MANUFACTURINGGRID 0.005 ;

LAYER OVERLAP
    TYPE OVERLAP ;
END OVERLAP

LAYER LOCKED
    TYPE MASTERSLICE ;
END LOCKED

LAYER LOCKED1
    TYPE MASTERSLICE ;
END LOCKED1

LAYER LOCKED2
    TYPE MASTERSLICE ;
END LOCKED2

LAYER GatPoly
    TYPE MASTERSLICE ;
END GatPoly

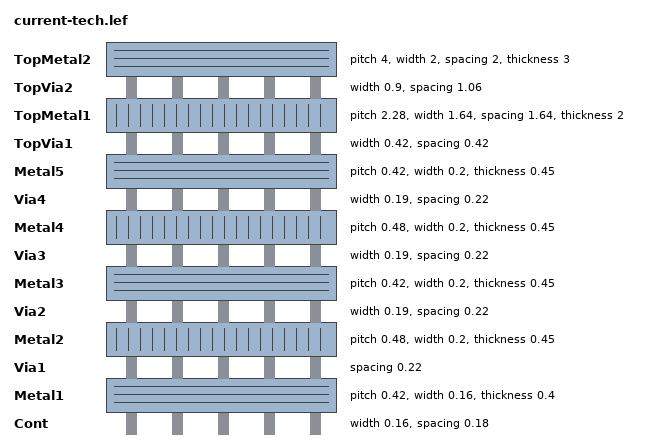
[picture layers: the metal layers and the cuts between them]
LAYER Cont
    TYPE CUT ;
    WIDTH 0.16 ;
    SPACING 0.18  ;
    ANTENNACUMAREARATIO 30 ;
    ANTENNACUMDIFFAREARATIO 10000 ;
    RESISTANCE 22 ;
END Cont

LAYER Metal1
    TYPE ROUTING ;
    PITCH 0.42 ;
    WIDTH 0.16 ;
    AREA 0.09 ;
    THICKNESS 0.4 ;
    MAXWIDTH 30 ;
SPACINGTABLE
  PARALLELRUNLENGTH 0.000 1.000 10.000
  WIDTH 0.000	 0.180 0.180 0.180
  WIDTH 0.300	 0.180 0.220 0.220
  WIDTH 10.000	 0.180 0.220 0.600 ;
    MINIMUMCUT 2  WIDTH 1.4 ;
    ANTENNACUMAREARATIO 200 ;
    ANTENNACUMDIFFAREARATIO  PWL ( ( 0 200 ) ( 0.159 200 ) ( 0.16 3200 ) ( 100 2e+06 ) ) ;
    DIRECTION HORIZONTAL ;
    RESISTANCE RPERSQ 0.135 ;
    CAPACITANCE CPERSQDIST 3.49e-05 ;
    EDGECAPACITANCE 3.16e-05 ;
END Metal1

LAYER Via1
    TYPE CUT ;
    SPACING 0.22  ;
    SPACING 0.29 ADJACENTCUTS 3 WITHIN 0.311  ;
    ANTENNAAREARATIO 20 ;
    ANTENNADIFFAREARATIO  PWL ( ( 0 20 ) ( 0.159 20 ) ( 0.16 80 ) ( 100 50000 ) ) ;
    RESISTANCE 20 ;
END Via1

LAYER Metal2
    TYPE ROUTING ;
    PITCH 0.48 ;
    WIDTH 0.2 ;
    WIREEXTENSION 0.1 ;
    AREA 0.144 ;
    THICKNESS 0.45 ;
    MAXWIDTH 30 ;
SPACINGTABLE
  PARALLELRUNLENGTH 0.000 1.000 10.000
  WIDTH 0.000	 0.210 0.210 0.210
  WIDTH 0.390	 0.210 0.240 0.240
  WIDTH 10.000	 0.210 0.240 0.600 ;
    MINIMUMCUT 2  WIDTH 1.4 ;
    ANTENNACUMAREARATIO 200 ;
    ANTENNACUMDIFFAREARATIO  PWL ( ( 0 200 ) ( 0.159 200 ) ( 0.16 3200 ) ( 100 2e+06 ) ) ;
    DIRECTION VERTICAL ;
    RESISTANCE RPERSQ 0.103 ;
    CAPACITANCE CPERSQDIST 1.81e-05 ;
    EDGECAPACITANCE 4.47e-05 ;
END Metal2

LAYER Via2
    TYPE CUT ;
    WIDTH 0.19 ;
    SPACING 0.22  ;
    SPACING 0.29 ADJACENTCUTS 3 WITHIN 0.311  ;
    ANTENNAAREARATIO 20 ;
    ANTENNADIFFAREARATIO  PWL ( ( 0 20 ) ( 0.159 20 ) ( 0.16 80 ) ( 100 50000 ) ) ;
    RESISTANCE 20 ;
END Via2

LAYER Metal3
    TYPE ROUTING ;
    PITCH 0.42 ;
    WIDTH 0.2 ;
    AREA 0.144 ;
    THICKNESS 0.45 ;
SPACINGTABLE
  PARALLELRUNLENGTH 0.000 1.000 10.000
  WIDTH 0.000	 0.210 0.210 0.210
  WIDTH 0.390	 0.210 0.240 0.240
  WIDTH 10.000	 0.210 0.240 0.600 ;
    MINIMUMCUT 2  WIDTH 1.4 ;
    ANTENNACUMAREARATIO 200 ;
    ANTENNACUMDIFFAREARATIO  PWL ( ( 0 200 ) ( 0.159 200 ) ( 0.16 3200 ) ( 100 2e+06 ) ) ;
    DIRECTION HORIZONTAL ;
    RESISTANCE RPERSQ 0.103 ;
    CAPACITANCE CPERSQDIST 1.2e-05 ;
    EDGECAPACITANCE 4.48e-05 ;
END Metal3

LAYER Via3
    TYPE CUT ;
    WIDTH 0.19 ;
    SPACING 0.22  ;
    SPACING 0.29 ADJACENTCUTS 3 WITHIN 0.311  ;
    ANTENNAAREARATIO 20 ;
    ANTENNADIFFAREARATIO  PWL ( ( 0 20 ) ( 0.159 20 ) ( 0.16 80 ) ( 100 50000 ) ) ;
    RESISTANCE 20 ;
END Via3

LAYER Metal4
    TYPE ROUTING ;
    PITCH 0.48 ;
    WIDTH 0.2 ;
    AREA 0.144 ;
    THICKNESS 0.45 ;
SPACINGTABLE
  PARALLELRUNLENGTH 0.000 1.000 10.000
  WIDTH 0.000	 0.210 0.210 0.210
  WIDTH 0.390	 0.210 0.240 0.240
  WIDTH 10.000	 0.210 0.240 0.600 ;
    MINIMUMCUT 2  WIDTH 1.4 ;
    ANTENNACUMAREARATIO 200 ;
    ANTENNACUMDIFFAREARATIO  PWL ( ( 0 200 ) ( 0.159 200 ) ( 0.16 3200 ) ( 100 2e+06 ) ) ;
    DIRECTION VERTICAL ;
    RESISTANCE RPERSQ 0.103 ;
    CAPACITANCE CPERSQDIST 8.94e-06 ;
    EDGECAPACITANCE 4.5e-05 ;
END Metal4

LAYER Via4
    TYPE CUT ;
    WIDTH 0.19 ;
    SPACING 0.22  ;
    SPACING 0.29 ADJACENTCUTS 3 WITHIN 0.311  ;
    ANTENNAAREARATIO 20 ;
    ANTENNADIFFAREARATIO  PWL ( ( 0 20 ) ( 0.159 20 ) ( 0.16 80 ) ( 100 50000 ) ) ;
    RESISTANCE 20 ;
END Via4

LAYER Metal5
    TYPE ROUTING ;
    PITCH 0.42 ;
    WIDTH 0.2 ;
    AREA 0.144 ;
    THICKNESS 0.45 ;
SPACINGTABLE
  PARALLELRUNLENGTH 0.000 1.000 10.000
  WIDTH 0.000	 0.210 0.210 0.210
  WIDTH 0.390	 0.210 0.240 0.240
  WIDTH 10.000	 0.210 0.240 0.600 ;
    MINIMUMCUT 2  WIDTH 1.4 ;
    ANTENNACUMAREARATIO 200 ;
    ANTENNACUMDIFFAREARATIO  PWL ( ( 0 200 ) ( 0.159 200 ) ( 0.16 3200 ) ( 100 2e+06 ) ) ;
    DIRECTION HORIZONTAL ;
    RESISTANCE RPERSQ 0.103 ;
    CAPACITANCE CPERSQDIST 7.13e-06 ;
    EDGECAPACITANCE 4.37e-05 ;
END Metal5

LAYER TopVia1
    TYPE CUT ;
    WIDTH 0.42 ;
    SPACING 0.42  ;
    ANTENNAAREARATIO 20 ;
    ANTENNADIFFAREARATIO  PWL ( ( 0 20 ) ( 0.159 20 ) ( 0.16 80 ) ( 100 50000 ) ) ;
    RESISTANCE 4 ;
END TopVia1

LAYER TopMetal1
    TYPE ROUTING ;
    PITCH 2.28 ;
    WIDTH 1.64 ;
    THICKNESS 2 ;
    SPACING 1.64  ;
    ANTENNACUMAREARATIO 200 ;
    ANTENNACUMDIFFAREARATIO  PWL ( ( 0 200 ) ( 0.159 200 ) ( 0.16 3200 ) ( 100 2e+06 ) ) ;
    DIRECTION VERTICAL ;
    RESISTANCE RPERSQ 0.021 ;
    CAPACITANCE CPERSQDIST 5.64e-06 ;
    EDGECAPACITANCE 5.08e-05 ;
END TopMetal1

LAYER TopVia2
    TYPE CUT ;
    WIDTH 0.9 ;
    SPACING 1.06  ;
    ANTENNAAREARATIO 20 ;
    ANTENNADIFFAREARATIO  PWL ( ( 0 20 ) ( 0.159 20 ) ( 0.16 80 ) ( 100 50000 ) ) ;
    RESISTANCE 2.2 ;
END TopVia2

LAYER TopMetal2
    TYPE ROUTING ;
    PITCH 4 ;
    WIDTH 2 ;
    THICKNESS 3 ;
    SPACING 2  ;
    ANTENNACUMAREARATIO 200 ;
    ANTENNACUMDIFFAREARATIO  PWL ( ( 0 200 ) ( 0.159 200 ) ( 0.16 3200 ) ( 100 2e+06 ) ) ;
    DIRECTION HORIZONTAL ;
    RESISTANCE RPERSQ 0.0145 ;
    CAPACITANCE CPERSQDIST 3.23e-06 ;
    EDGECAPACITANCE 4.18e-05 ;
END TopMetal2

VIA Via1_XX DEFAULT
    RESISTANCE 20 ;
    LAYER Metal1 ;
      RECT  -0.145 -0.105 0.145 0.105 ;
    LAYER Via1 ;
      RECT  -0.095 -0.095 0.095 0.095 ;
    LAYER Metal2 ;
      RECT  -0.145 -0.1 0.145 0.1 ;
END Via1_XX

VIA Via1_XX_s DEFAULT
    RESISTANCE 20 ;
    LAYER Metal1 ;
      RECT  -0.145 -0.105 0.145 0.105 ;
    LAYER Via1 ;
      RECT  -0.095 -0.095 0.095 0.095 ;
    LAYER Metal2 ;
      RECT  -0.36 -0.1 0.36 0.1 ;
END Via1_XX_s

VIA Via1_XY DEFAULT
    RESISTANCE 20 ;
    LAYER Metal1 ;
      RECT  -0.145 -0.105 0.145 0.105 ;
    LAYER Via1 ;
      RECT  -0.095 -0.095 0.095 0.095 ;
    LAYER Metal2 ;
      RECT  -0.1 -0.145 0.1 0.145 ;
END Via1_XY

VIA Via1_XY_s DEFAULT
    RESISTANCE 20 ;
    LAYER Metal1 ;
      RECT  -0.145 -0.105 0.145 0.105 ;
    LAYER Via1 ;
      RECT  -0.095 -0.095 0.095 0.095 ;
    LAYER Metal2 ;
      RECT  -0.1 -0.36 0.1 0.36 ;
END Via1_XY_s

VIA Via1_YX DEFAULT
    RESISTANCE 20 ;
    LAYER Metal1 ;
      RECT  -0.105 -0.145 0.105 0.145 ;
    LAYER Via1 ;
      RECT  -0.095 -0.095 0.095 0.095 ;
    LAYER Metal2 ;
      RECT  -0.145 -0.1 0.145 0.1 ;
END Via1_YX

VIA Via1_YX_s DEFAULT
    RESISTANCE 20 ;
    LAYER Metal1 ;
      RECT  -0.105 -0.145 0.105 0.145 ;
    LAYER Via1 ;
      RECT  -0.095 -0.095 0.095 0.095 ;
    LAYER Metal2 ;
      RECT  -0.36 -0.1 0.36 0.1 ;
END Via1_YX_s

VIA Via1_YY DEFAULT
    RESISTANCE 20 ;
    LAYER Metal1 ;
      RECT  -0.105 -0.145 0.105 0.145 ;
    LAYER Via1 ;
      RECT  -0.095 -0.095 0.095 0.095 ;
    LAYER Metal2 ;
      RECT  -0.1 -0.145 0.1 0.145 ;
END Via1_YY

VIA Via1_YY_s DEFAULT
    RESISTANCE 20 ;
    LAYER Metal1 ;
      RECT  -0.105 -0.145 0.105 0.145 ;
    LAYER Via1 ;
      RECT  -0.095 -0.095 0.095 0.095 ;
    LAYER Metal2 ;
      RECT  -0.1 -0.36 0.1 0.36 ;
END Via1_YY_s

VIA Via1_s DEFAULT
    RESISTANCE 20 ;
    LAYER Metal1 ;
      RECT  -0.145 -0.145 0.145 0.145 ;
    LAYER Via1 ;
      RECT  -0.095 -0.095 0.095 0.095 ;
    LAYER Metal2 ;
      RECT  -0.19 -0.19 0.19 0.19 ;
END Via1_s

VIA Via1_DC1B DEFAULT
    RESISTANCE 20 ;
    LAYER Metal1 ;
      RECT  -0.105 -0.145 0.105 0.555 ;
    LAYER Via1 ;
      RECT  -0.095 -0.095 0.095 0.095 ;
      RECT  -0.095 0.315 0.095 0.505 ;
    LAYER Metal2 ;
      RECT  -0.1 -0.155 0.1 0.565 ;
END Via1_DC1B

VIA Via1_DC1T DEFAULT
    RESISTANCE 20 ;
    LAYER Metal1 ;
      RECT  -0.105 -0.555 0.105 0.145 ;
    LAYER Via1 ;
      RECT  -0.095 -0.095 0.095 0.095 ;
      RECT  -0.095 -0.505 0.095 -0.315 ;
    LAYER Metal2 ;
      RECT  -0.1 -0.565 0.1 0.155 ;
END Via1_DC1T

VIA Via1_DC1L DEFAULT
    RESISTANCE 20 ;
    LAYER Metal1 ;
      RECT  -0.145 -0.105 0.555 0.105 ;
    LAYER Via1 ;
      RECT  -0.095 -0.095 0.095 0.095 ;
      RECT  0.315 -0.095 0.505 0.095 ;
    LAYER Metal2 ;
      RECT  -0.155 -0.1 0.565 0.1 ;
END Via1_DC1L

VIA Via1_DC1R DEFAULT
    RESISTANCE 20 ;
    LAYER Metal1 ;
      RECT  -0.555 -0.105 0.145 0.105 ;
    LAYER Via1 ;
      RECT  -0.095 -0.095 0.095 0.095 ;
      RECT  -0.505 -0.095 -0.315 0.095 ;
    LAYER Metal2 ;
      RECT  -0.565 -0.1 0.155 0.1 ;
END Via1_DC1R

VIA Via1_DC2B DEFAULT
    RESISTANCE 20 ;
    LAYER Metal1 ;
      RECT  -0.105 -0.145 0.105 0.555 ;
    LAYER Via1 ;
      RECT  -0.095 -0.095 0.095 0.095 ;
      RECT  -0.095 0.315 0.095 0.505 ;
    LAYER Metal2 ;
      RECT  -0.145 -0.105 0.145 0.515 ;
END Via1_DC2B

VIA Via1_DC2T DEFAULT
    RESISTANCE 20 ;
    LAYER Metal1 ;
      RECT  -0.105 -0.555 0.105 0.145 ;
    LAYER Via1 ;
      RECT  -0.095 -0.095 0.095 0.095 ;
      RECT  -0.095 -0.505 0.095 -0.315 ;
    LAYER Metal2 ;
      RECT  -0.145 -0.515 0.145 0.105 ;
END Via1_DC2T

VIA Via1_DC2L DEFAULT
    RESISTANCE 20 ;
    LAYER Metal1 ;
      RECT  -0.1 -0.145 0.52 0.145 ;
    LAYER Via1 ;
      RECT  -0.095 -0.095 0.095 0.095 ;
      RECT  0.32 -0.095 0.51 0.095 ;
    LAYER Metal2 ;
      RECT  -0.1 -0.145 0.52 0.145 ;
END Via1_DC2L

VIA Via1_DC2R DEFAULT
    RESISTANCE 20 ;
    LAYER Metal1 ;
      RECT  -0.555 -0.105 0.145 0.105 ;
    LAYER Via1 ;
      RECT  -0.095 -0.095 0.095 0.095 ;
      RECT  -0.505 -0.095 -0.315 0.095 ;
    LAYER Metal2 ;
      RECT  -0.515 -0.145 0.105 0.145 ;
END Via1_DC2R

VIA Via2_XX DEFAULT
    RESISTANCE 20 ;
    LAYER Metal2 ;
      RECT  -0.145 -0.105 0.145 0.105 ;
    LAYER Via2 ;
      RECT  -0.095 -0.095 0.095 0.095 ;
    LAYER Metal3 ;
      RECT  -0.145 -0.1 0.145 0.1 ;
END Via2_XX

VIA Via2_XX_s DEFAULT
    RESISTANCE 20 ;
    LAYER Metal2 ;
      RECT  -0.145 -0.105 0.145 0.105 ;
    LAYER Via2 ;
      RECT  -0.095 -0.095 0.095 0.095 ;
    LAYER Metal3 ;
      RECT  -0.36 -0.1 0.36 0.1 ;
END Via2_XX_s

VIA Via2_XY DEFAULT
    RESISTANCE 20 ;
    LAYER Metal2 ;
      RECT  -0.145 -0.105 0.145 0.105 ;
    LAYER Via2 ;
      RECT  -0.095 -0.095 0.095 0.095 ;
    LAYER Metal3 ;
      RECT  -0.1 -0.145 0.1 0.145 ;
END Via2_XY

VIA Via2_XY_s DEFAULT
    RESISTANCE 20 ;
    LAYER Metal2 ;
      RECT  -0.145 -0.105 0.145 0.105 ;
    LAYER Via2 ;
      RECT  -0.095 -0.095 0.095 0.095 ;
    LAYER Metal3 ;
      RECT  -0.1 -0.36 0.1 0.36 ;
END Via2_XY_s

VIA Via2_YX DEFAULT
    RESISTANCE 20 ;
    LAYER Metal2 ;
      RECT  -0.105 -0.145 0.105 0.145 ;
    LAYER Via2 ;
      RECT  -0.095 -0.095 0.095 0.095 ;
    LAYER Metal3 ;
      RECT  -0.145 -0.1 0.145 0.1 ;
END Via2_YX

VIA Via2_YX_s DEFAULT
    RESISTANCE 20 ;
    LAYER Metal2 ;
      RECT  -0.105 -0.145 0.105 0.145 ;
    LAYER Via2 ;
      RECT  -0.095 -0.095 0.095 0.095 ;
    LAYER Metal3 ;
      RECT  -0.36 -0.1 0.36 0.1 ;
END Via2_YX_s

VIA Via2_YY DEFAULT
    RESISTANCE 20 ;
    LAYER Metal2 ;
      RECT  -0.105 -0.145 0.105 0.145 ;
    LAYER Via2 ;
      RECT  -0.095 -0.095 0.095 0.095 ;
    LAYER Metal3 ;
      RECT  -0.1 -0.145 0.1 0.145 ;
END Via2_YY

VIA Via2_YY_s DEFAULT
    RESISTANCE 20 ;
    LAYER Metal2 ;
      RECT  -0.105 -0.145 0.105 0.145 ;
    LAYER Via2 ;
      RECT  -0.095 -0.095 0.095 0.095 ;
    LAYER Metal3 ;
      RECT  -0.1 -0.36 0.1 0.36 ;
END Via2_YY_s

VIA Via2_s DEFAULT
    RESISTANCE 20 ;
    LAYER Metal2 ;
      RECT  -0.145 -0.145 0.145 0.145 ;
    LAYER Via2 ;
      RECT  -0.095 -0.095 0.095 0.095 ;
    LAYER Metal3 ;
      RECT  -0.19 -0.19 0.19 0.19 ;
END Via2_s

VIA Via2_DC1B DEFAULT
    RESISTANCE 20 ;
    LAYER Metal2 ;
      RECT  -0.105 -0.145 0.105 0.555 ;
    LAYER Via2 ;
      RECT  -0.095 -0.095 0.095 0.095 ;
      RECT  -0.095 0.315 0.095 0.505 ;
    LAYER Metal3 ;
      RECT  -0.1 -0.155 0.1 0.565 ;
END Via2_DC1B

VIA Via2_DC1T DEFAULT
    RESISTANCE 20 ;
    LAYER Metal2 ;
      RECT  -0.105 -0.555 0.105 0.145 ;
    LAYER Via2 ;
      RECT  -0.095 -0.095 0.095 0.095 ;
      RECT  -0.095 -0.505 0.095 -0.315 ;
    LAYER Metal3 ;
      RECT  -0.1 -0.565 0.1 0.155 ;
END Via2_DC1T

VIA Via2_DC1L DEFAULT
    RESISTANCE 20 ;
    LAYER Metal2 ;
      RECT  -0.145 -0.105 0.555 0.105 ;
    LAYER Via2 ;
      RECT  -0.095 -0.095 0.095 0.095 ;
      RECT  0.315 -0.095 0.505 0.095 ;
    LAYER Metal3 ;
      RECT  -0.155 -0.1 0.565 0.1 ;
END Via2_DC1L

VIA Via2_DC1R DEFAULT
    RESISTANCE 20 ;
    LAYER Metal2 ;
      RECT  -0.555 -0.105 0.145 0.105 ;
    LAYER Via2 ;
      RECT  -0.095 -0.095 0.095 0.095 ;
      RECT  -0.505 -0.095 -0.315 0.095 ;
    LAYER Metal3 ;
      RECT  -0.565 -0.1 0.155 0.1 ;
END Via2_DC1R

VIA Via2_DC2B DEFAULT
    RESISTANCE 20 ;
    LAYER Metal2 ;
      RECT  -0.105 -0.145 0.105 0.555 ;
    LAYER Via2 ;
      RECT  -0.095 -0.095 0.095 0.095 ;
      RECT  -0.095 0.315 0.095 0.505 ;
    LAYER Metal3 ;
      RECT  -0.145 -0.105 0.145 0.515 ;
END Via2_DC2B

VIA Via2_DC2T DEFAULT
    RESISTANCE 20 ;
    LAYER Metal2 ;
      RECT  -0.105 -0.555 0.105 0.145 ;
    LAYER Via2 ;
      RECT  -0.095 -0.095 0.095 0.095 ;
      RECT  -0.095 -0.505 0.095 -0.315 ;
    LAYER Metal3 ;
      RECT  -0.145 -0.515 0.145 0.105 ;
END Via2_DC2T

VIA Via2_DC2L DEFAULT
    RESISTANCE 20 ;
    LAYER Metal2 ;
      RECT  -0.1 -0.145 0.52 0.145 ;
    LAYER Via2 ;
      RECT  -0.095 -0.095 0.095 0.095 ;
      RECT  0.32 -0.095 0.51 0.095 ;
    LAYER Metal3 ;
      RECT  -0.1 -0.145 0.52 0.145 ;
END Via2_DC2L

VIA Via2_DC2R DEFAULT
    RESISTANCE 20 ;
    LAYER Metal2 ;
      RECT  -0.555 -0.105 0.145 0.105 ;
    LAYER Via2 ;
      RECT  -0.095 -0.095 0.095 0.095 ;
      RECT  -0.505 -0.095 -0.315 0.095 ;
    LAYER Metal3 ;
      RECT  -0.515 -0.145 0.105 0.145 ;
END Via2_DC2R

VIA Via3_XX DEFAULT
    RESISTANCE 20 ;
    LAYER Metal3 ;
      RECT  -0.145 -0.105 0.145 0.105 ;
    LAYER Via3 ;
      RECT  -0.095 -0.095 0.095 0.095 ;
    LAYER Metal4 ;
      RECT  -0.145 -0.1 0.145 0.1 ;
END Via3_XX

VIA Via3_XX_s DEFAULT
    RESISTANCE 20 ;
    LAYER Metal3 ;
      RECT  -0.145 -0.105 0.145 0.105 ;
    LAYER Via3 ;
      RECT  -0.095 -0.095 0.095 0.095 ;
    LAYER Metal4 ;
      RECT  -0.36 -0.1 0.36 0.1 ;
END Via3_XX_s

VIA Via3_XY DEFAULT
    RESISTANCE 20 ;
    LAYER Metal3 ;
      RECT  -0.145 -0.105 0.145 0.105 ;
    LAYER Via3 ;
      RECT  -0.095 -0.095 0.095 0.095 ;
    LAYER Metal4 ;
      RECT  -0.1 -0.145 0.1 0.145 ;
END Via3_XY

VIA Via3_XY_s DEFAULT
    RESISTANCE 20 ;
    LAYER Metal3 ;
      RECT  -0.145 -0.105 0.145 0.105 ;
    LAYER Via3 ;
      RECT  -0.095 -0.095 0.095 0.095 ;
    LAYER Metal4 ;
      RECT  -0.1 -0.36 0.1 0.36 ;
END Via3_XY_s

VIA Via3_YX DEFAULT
    RESISTANCE 20 ;
    LAYER Metal3 ;
      RECT  -0.105 -0.145 0.105 0.145 ;
    LAYER Via3 ;
      RECT  -0.095 -0.095 0.095 0.095 ;
    LAYER Metal4 ;
      RECT  -0.145 -0.1 0.145 0.1 ;
END Via3_YX

VIA Via3_YX_s DEFAULT
    RESISTANCE 20 ;
    LAYER Metal3 ;
      RECT  -0.105 -0.145 0.105 0.145 ;
    LAYER Via3 ;
      RECT  -0.095 -0.095 0.095 0.095 ;
    LAYER Metal4 ;
      RECT  -0.36 -0.1 0.36 0.1 ;
END Via3_YX_s

VIA Via3_YY DEFAULT
    RESISTANCE 20 ;
    LAYER Metal3 ;
      RECT  -0.105 -0.145 0.105 0.145 ;
    LAYER Via3 ;
      RECT  -0.095 -0.095 0.095 0.095 ;
    LAYER Metal4 ;
      RECT  -0.1 -0.145 0.1 0.145 ;
END Via3_YY

VIA Via3_YY_s DEFAULT
    RESISTANCE 20 ;
    LAYER Metal3 ;
      RECT  -0.105 -0.145 0.105 0.145 ;
    LAYER Via3 ;
      RECT  -0.095 -0.095 0.095 0.095 ;
    LAYER Metal4 ;
      RECT  -0.1 -0.36 0.1 0.36 ;
END Via3_YY_s

VIA Via3_s DEFAULT
    RESISTANCE 20 ;
    LAYER Metal3 ;
      RECT  -0.145 -0.145 0.145 0.145 ;
    LAYER Via3 ;
      RECT  -0.095 -0.095 0.095 0.095 ;
    LAYER Metal4 ;
      RECT  -0.19 -0.19 0.19 0.19 ;
END Via3_s

VIA Via3_DC1B DEFAULT
    RESISTANCE 20 ;
    LAYER Metal3 ;
      RECT  -0.105 -0.145 0.105 0.555 ;
    LAYER Via3 ;
      RECT  -0.095 -0.095 0.095 0.095 ;
      RECT  -0.095 0.315 0.095 0.505 ;
    LAYER Metal4 ;
      RECT  -0.1 -0.155 0.1 0.565 ;
END Via3_DC1B

VIA Via3_DC1T DEFAULT
    RESISTANCE 20 ;
    LAYER Metal3 ;
      RECT  -0.105 -0.555 0.105 0.145 ;
    LAYER Via3 ;
      RECT  -0.095 -0.095 0.095 0.095 ;
      RECT  -0.095 -0.505 0.095 -0.315 ;
    LAYER Metal4 ;
      RECT  -0.1 -0.565 0.1 0.155 ;
END Via3_DC1T

VIA Via3_DC1L DEFAULT
    RESISTANCE 20 ;
    LAYER Metal3 ;
      RECT  -0.145 -0.105 0.555 0.105 ;
    LAYER Via3 ;
      RECT  -0.095 -0.095 0.095 0.095 ;
      RECT  0.315 -0.095 0.505 0.095 ;
    LAYER Metal4 ;
      RECT  -0.155 -0.1 0.565 0.1 ;
END Via3_DC1L

VIA Via3_DC1R DEFAULT
    RESISTANCE 20 ;
    LAYER Metal3 ;
      RECT  -0.555 -0.105 0.145 0.105 ;
    LAYER Via3 ;
      RECT  -0.095 -0.095 0.095 0.095 ;
      RECT  -0.505 -0.095 -0.315 0.095 ;
    LAYER Metal4 ;
      RECT  -0.565 -0.1 0.155 0.1 ;
END Via3_DC1R

VIA Via3_DC2B DEFAULT
    RESISTANCE 20 ;
    LAYER Metal3 ;
      RECT  -0.105 -0.145 0.105 0.555 ;
    LAYER Via3 ;
      RECT  -0.095 -0.095 0.095 0.095 ;
      RECT  -0.095 0.315 0.095 0.505 ;
    LAYER Metal4 ;
      RECT  -0.145 -0.105 0.145 0.515 ;
END Via3_DC2B

VIA Via3_DC2T DEFAULT
    RESISTANCE 20 ;
    LAYER Metal3 ;
      RECT  -0.105 -0.555 0.105 0.145 ;
    LAYER Via3 ;
      RECT  -0.095 -0.095 0.095 0.095 ;
      RECT  -0.095 -0.505 0.095 -0.315 ;
    LAYER Metal4 ;
      RECT  -0.145 -0.515 0.145 0.105 ;
END Via3_DC2T

VIA Via3_DC2L DEFAULT
    RESISTANCE 20 ;
    LAYER Metal3 ;
      RECT  -0.1 -0.145 0.52 0.145 ;
    LAYER Via3 ;
      RECT  -0.095 -0.095 0.095 0.095 ;
      RECT  0.32 -0.095 0.51 0.095 ;
    LAYER Metal4 ;
      RECT  -0.1 -0.145 0.52 0.145 ;
END Via3_DC2L

VIA Via3_DC2R DEFAULT
    RESISTANCE 20 ;
    LAYER Metal3 ;
      RECT  -0.555 -0.105 0.145 0.105 ;
    LAYER Via3 ;
      RECT  -0.095 -0.095 0.095 0.095 ;
      RECT  -0.505 -0.095 -0.315 0.095 ;
    LAYER Metal4 ;
      RECT  -0.515 -0.145 0.105 0.145 ;
END Via3_DC2R

VIA Via4_XX DEFAULT
    RESISTANCE 20 ;
    LAYER Metal4 ;
      RECT  -0.145 -0.105 0.145 0.105 ;
    LAYER Via4 ;
      RECT  -0.095 -0.095 0.095 0.095 ;
    LAYER Metal5 ;
      RECT  -0.145 -0.1 0.145 0.1 ;
END Via4_XX

VIA Via4_XX_s DEFAULT
    RESISTANCE 20 ;
    LAYER Metal4 ;
      RECT  -0.145 -0.105 0.145 0.105 ;
    LAYER Via4 ;
      RECT  -0.095 -0.095 0.095 0.095 ;
    LAYER Metal5 ;
      RECT  -0.36 -0.1 0.36 0.1 ;
END Via4_XX_s

VIA Via4_XY DEFAULT
    RESISTANCE 20 ;
    LAYER Metal4 ;
      RECT  -0.145 -0.105 0.145 0.105 ;
    LAYER Via4 ;
      RECT  -0.095 -0.095 0.095 0.095 ;
    LAYER Metal5 ;
      RECT  -0.1 -0.145 0.1 0.145 ;
END Via4_XY

VIA Via4_XY_s DEFAULT
    RESISTANCE 20 ;
    LAYER Metal4 ;
      RECT  -0.145 -0.105 0.145 0.105 ;
    LAYER Via4 ;
      RECT  -0.095 -0.095 0.095 0.095 ;
    LAYER Metal5 ;
      RECT  -0.1 -0.36 0.1 0.36 ;
END Via4_XY_s

VIA Via4_YX DEFAULT
    RESISTANCE 20 ;
    LAYER Metal4 ;
      RECT  -0.105 -0.145 0.105 0.145 ;
    LAYER Via4 ;
      RECT  -0.095 -0.095 0.095 0.095 ;
    LAYER Metal5 ;
      RECT  -0.145 -0.1 0.145 0.1 ;
END Via4_YX

VIA Via4_YX_s DEFAULT
    RESISTANCE 20 ;
    LAYER Metal4 ;
      RECT  -0.105 -0.145 0.105 0.145 ;
    LAYER Via4 ;
      RECT  -0.095 -0.095 0.095 0.095 ;
    LAYER Metal5 ;
      RECT  -0.36 -0.1 0.36 0.1 ;
END Via4_YX_s

VIA Via4_YY DEFAULT
    RESISTANCE 20 ;
    LAYER Metal4 ;
      RECT  -0.105 -0.145 0.105 0.145 ;
    LAYER Via4 ;
      RECT  -0.095 -0.095 0.095 0.095 ;
    LAYER Metal5 ;
      RECT  -0.1 -0.145 0.1 0.145 ;
END Via4_YY

VIA Via4_YY_s DEFAULT
    RESISTANCE 20 ;
    LAYER Metal4 ;
      RECT  -0.105 -0.145 0.105 0.145 ;
    LAYER Via4 ;
      RECT  -0.095 -0.095 0.095 0.095 ;
    LAYER Metal5 ;
      RECT  -0.1 -0.36 0.1 0.36 ;
END Via4_YY_s

VIA Via4_s DEFAULT
    RESISTANCE 20 ;
    LAYER Metal4 ;
      RECT  -0.145 -0.145 0.145 0.145 ;
    LAYER Via4 ;
      RECT  -0.095 -0.095 0.095 0.095 ;
    LAYER Metal5 ;
      RECT  -0.19 -0.19 0.19 0.19 ;
END Via4_s

VIA Via4_DC1B DEFAULT
    RESISTANCE 20 ;
    LAYER Metal4 ;
      RECT  -0.105 -0.145 0.105 0.555 ;
    LAYER Via4 ;
      RECT  -0.095 -0.095 0.095 0.095 ;
      RECT  -0.095 0.315 0.095 0.505 ;
    LAYER Metal5 ;
      RECT  -0.1 -0.155 0.1 0.565 ;
END Via4_DC1B

VIA Via4_DC1T DEFAULT
    RESISTANCE 20 ;
    LAYER Metal4 ;
      RECT  -0.105 -0.555 0.105 0.145 ;
    LAYER Via4 ;
      RECT  -0.095 -0.095 0.095 0.095 ;
      RECT  -0.095 -0.505 0.095 -0.315 ;
    LAYER Metal5 ;
      RECT  -0.1 -0.565 0.1 0.155 ;
END Via4_DC1T

VIA Via4_DC1L DEFAULT
    RESISTANCE 20 ;
    LAYER Metal4 ;
      RECT  -0.145 -0.105 0.555 0.105 ;
    LAYER Via4 ;
      RECT  -0.095 -0.095 0.095 0.095 ;
      RECT  0.315 -0.095 0.505 0.095 ;
    LAYER Metal5 ;
      RECT  -0.155 -0.1 0.565 0.1 ;
END Via4_DC1L

VIA Via4_DC1R DEFAULT
    RESISTANCE 20 ;
    LAYER Metal4 ;
      RECT  -0.555 -0.105 0.145 0.105 ;
    LAYER Via4 ;
      RECT  -0.095 -0.095 0.095 0.095 ;
      RECT  -0.505 -0.095 -0.315 0.095 ;
    LAYER Metal5 ;
      RECT  -0.565 -0.1 0.155 0.1 ;
END Via4_DC1R

VIA Via4_DC2B DEFAULT
    RESISTANCE 20 ;
    LAYER Metal4 ;
      RECT  -0.105 -0.145 0.105 0.555 ;
    LAYER Via4 ;
      RECT  -0.095 -0.095 0.095 0.095 ;
      RECT  -0.095 0.315 0.095 0.505 ;
    LAYER Metal5 ;
      RECT  -0.145 -0.105 0.145 0.515 ;
END Via4_DC2B

VIA Via4_DC2T DEFAULT
    RESISTANCE 20 ;
    LAYER Metal4 ;
      RECT  -0.105 -0.555 0.105 0.145 ;
    LAYER Via4 ;
      RECT  -0.095 -0.095 0.095 0.095 ;
      RECT  -0.095 -0.505 0.095 -0.315 ;
    LAYER Metal5 ;
      RECT  -0.145 -0.515 0.145 0.105 ;
END Via4_DC2T

VIA Via4_DC2L DEFAULT
    RESISTANCE 20 ;
    LAYER Metal4 ;
      RECT  -0.1 -0.145 0.52 0.145 ;
    LAYER Via4 ;
      RECT  -0.095 -0.095 0.095 0.095 ;
      RECT  0.32 -0.095 0.51 0.095 ;
    LAYER Metal5 ;
      RECT  -0.1 -0.145 0.52 0.145 ;
END Via4_DC2L

VIA Via4_DC2R DEFAULT
    RESISTANCE 20 ;
    LAYER Metal4 ;
      RECT  -0.555 -0.105 0.145 0.105 ;
    LAYER Via4 ;
      RECT  -0.095 -0.095 0.095 0.095 ;
      RECT  -0.505 -0.095 -0.315 0.095 ;
    LAYER Metal5 ;
      RECT  -0.515 -0.145 0.105 0.145 ;
END Via4_DC2R

VIA TopVia1EWNS DEFAULT
    RESISTANCE 4 ;
    LAYER Metal5 ;
      RECT  -0.31 -0.31 0.31 0.31 ;
    LAYER TopVia1 ;
      RECT  -0.21 -0.21 0.21 0.21 ;
    LAYER TopMetal1 ;
      RECT  -0.75 -0.75 0.75 0.75 ;
END TopVia1EWNS

VIA TopVia2EWNS DEFAULT
    RESISTANCE 2.2 ;
    LAYER TopMetal1 ;
      RECT  -0.95 -0.95 0.95 0.95 ;
    LAYER TopVia2 ;
      RECT  -0.45 -0.45 0.45 0.45 ;
    LAYER TopMetal2 ;
      RECT  -0.95 -0.95 0.95 0.95 ;
END TopVia2EWNS

VIARULE via1Array GENERATE 
    LAYER Metal1 ;
      ENCLOSURE 0.05 0.01 ;
    LAYER Metal2 ;
      ENCLOSURE 0.05 0.005 ;
    LAYER Via1 ;
      RECT  -0.095 -0.095  0.095 0.095  ;
      SPACING 0.48 BY 0.48 ;
      RESISTANCE 20 ;
END via1Array

VIARULE via2Array GENERATE 
    LAYER Metal2 ;
      ENCLOSURE 0.05 0.005 ;
    LAYER Metal3 ;
      ENCLOSURE 0.05 0.005 ;
    LAYER Via2 ;
      RECT  -0.095 -0.095  0.095 0.095  ;
      SPACING 0.48 BY 0.48 ;
      RESISTANCE 20 ;
END via2Array

VIARULE via3Array GENERATE 
    LAYER Metal3 ;
      ENCLOSURE 0.05 0.005 ;
    LAYER Metal4 ;
      ENCLOSURE 0.05 0.005 ;
    LAYER Via3 ;
      RECT  -0.095 -0.095  0.095 0.095  ;
      SPACING 0.48 BY 0.48 ;
      RESISTANCE 20 ;
END via3Array

VIARULE via4Array GENERATE 
    LAYER Metal4 ;
      ENCLOSURE 0.05 0.005 ;
    LAYER Metal5 ;
      ENCLOSURE 0.05 0.005 ;
    LAYER Via4 ;
      RECT  -0.095 -0.095  0.095 0.095  ;
      SPACING 0.48 BY 0.48 ;
      RESISTANCE 20 ;
END via4Array

VIARULE viagen56 GENERATE 
    LAYER Metal5 ;
      ENCLOSURE 0 0 ;
    LAYER TopMetal1 ;
      ENCLOSURE 0.61 0.61 ;
    LAYER TopVia1 ;
      RECT  -0.21 -0.21  0.21 0.21  ;
      SPACING 0.84 BY 0.84 ;
      RESISTANCE 4 ;
END viagen56

VIARULE viagen67 GENERATE 
    LAYER TopMetal1 ;
      ENCLOSURE 0.5 0.5 ;
    LAYER TopMetal2 ;
      ENCLOSURE 0.55 0.55 ;
    LAYER TopVia2 ;
      RECT  -0.45 -0.45  0.45 0.45  ;
      SPACING 1.96 BY 1.96 ;
      RESISTANCE 2.2 ;
END viagen67
END LIBRARY
